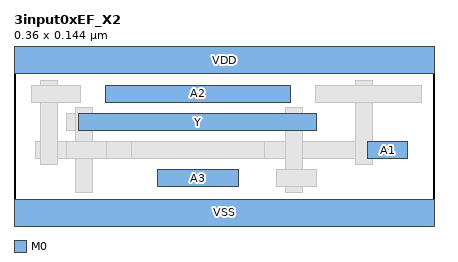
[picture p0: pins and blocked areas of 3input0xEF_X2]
MACRO 3input0xEF_X2
  CLASS CORE ;
  ORIGIN 0 0 ;
  FOREIGN 3input0xEF_X2 0 0 ;
  SIZE 0.3600 BY 0.1440 ;
  SYMMETRY X Y ;
  SITE coresite ;
  PIN A1
    DIRECTION INPUT ;
    USE SIGNAL ;
    PORT
      LAYER M0 ;
        RECT 0.3030 0.0530 0.3375 0.0670 ;
    END
  END A1
  PIN A2
    DIRECTION INPUT ;
    USE SIGNAL ;
    PORT
      LAYER M0 ;
        RECT 0.0780 0.1010 0.2370 0.1150 ;
    END
  END A2
  PIN A3
    DIRECTION INPUT ;
    USE SIGNAL ;
    PORT
      LAYER M0 ;
        RECT 0.1230 0.0290 0.1920 0.0430 ;
    END
  END A3
  PIN Y
    DIRECTION OUTPUT ;
    USE SIGNAL ;
    PORT
      LAYER M0 ;
        RECT 0.0555 0.0770 0.2595 0.0910 ;
    END
  END Y
  PIN VDD
    DIRECTION INOUT ;
    USE POWER ;
    SHAPE ABUTMENT ;
    PORT
      LAYER M0 ;
        RECT 0.0000 0.1260 0.3600 0.1620 ;
    END
  END VDD
  PIN VSS
    DIRECTION INOUT ;
    USE GROUND ;
    SHAPE ABUTMENT ;
    PORT
      LAYER M0 ;
        RECT 0.0000 -0.0180 0.3600 0.0180 ;
    END
  END VSS
  OBS
    LAYER M2 ;
      RECT 0.0180 0.0530 0.3150 0.0670 ;
      RECT 0.0450 0.0770 0.2520 0.0910 ;
    LAYER V1 ;
      RECT 0.0230 0.0530 0.0370 0.0670 ;
      RECT 0.2930 0.0530 0.3070 0.0670 ;
      RECT 0.0530 0.0770 0.0670 0.0910 ;
      RECT 0.2330 0.0770 0.2470 0.0910 ;
    LAYER M1 ;
      RECT 0.0525 0.0240 0.0675 0.0960 ;
      RECT 0.2325 0.0240 0.2475 0.0960 ;
      RECT 0.0225 0.0480 0.0375 0.1200 ;
      RECT 0.2925 0.0480 0.3075 0.1200 ;
    LAYER V0 ;
      RECT 0.0230 0.1010 0.0370 0.1150 ;
      RECT 0.2930 0.1010 0.3070 0.1150 ;
      RECT 0.0530 0.0530 0.0670 0.0670 ;
      RECT 0.2330 0.0290 0.2470 0.0430 ;
    LAYER M0 ;
      RECT 0.2250 0.0290 0.2595 0.0430 ;
      RECT 0.0450 0.0530 0.0795 0.0670 ;
      RECT 0.1005 0.0530 0.2145 0.0670 ;
      RECT 0.0150 0.1010 0.0570 0.1150 ;
      RECT 0.2580 0.1010 0.3495 0.1150 ;
  END
END 3input0xEF_X2
